###############################################################
#  Generated by:      Cadence Innovus 21.35-s114_1
#  OS:                Linux x86_64(Host ID pc231.ee.hacettepe.edu.tr)
#  Generated on:      Wed Dec 24 14:22:01 2025
#  Design:            protection_macro
#  Command:           write_lef_abstract -5.7 outputs/protection_macro/protection_macro.lef
###############################################################

VERSION 5.7 ;

BUSBITCHARS "[]" ;
DIVIDERCHAR "/" ;

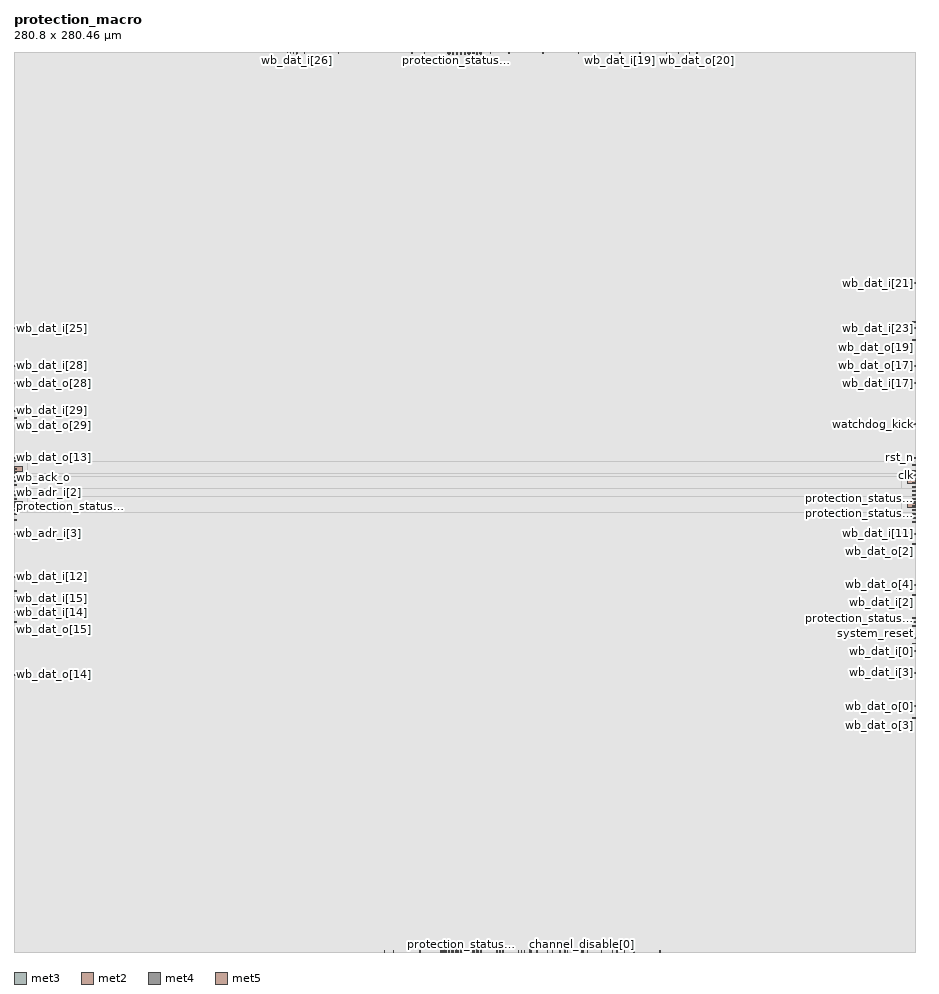
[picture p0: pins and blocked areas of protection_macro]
MACRO protection_macro
  CLASS BLOCK ;
  SIZE 280.800000 BY 280.460000 ;
  FOREIGN protection_macro 0.000000 0.000000 ;
  ORIGIN 0 0 ;
  SYMMETRY X Y R90 ;
  PIN clk
    DIRECTION INPUT ;
    USE SIGNAL ;
    PORT
      LAYER met3 ;
        RECT 280.000000 148.450000 280.800000 148.750000 ;
    END
  END clk
  PIN rst_n
    DIRECTION INPUT ;
    USE SIGNAL ;
    PORT
      LAYER met3 ;
        RECT 280.000000 151.500000 280.800000 151.800000 ;
    END
  END rst_n
  PIN wb_adr_i[31]
    DIRECTION INPUT ;
    USE SIGNAL ;
    PORT
      LAYER met2 ;
        RECT 142.250000 279.975000 142.390000 280.460000 ;
    END
  END wb_adr_i[31]
  PIN wb_adr_i[30]
    DIRECTION INPUT ;
    USE SIGNAL ;
    PORT
      LAYER met2 ;
        RECT 138.410000 0.000000 138.550000 0.485000 ;
    END
  END wb_adr_i[30]
  PIN wb_adr_i[29]
    DIRECTION INPUT ;
    USE SIGNAL ;
    PORT
      LAYER met2 ;
        RECT 142.250000 0.000000 142.390000 0.485000 ;
    END
  END wb_adr_i[29]
  PIN wb_adr_i[28]
    DIRECTION INPUT ;
    USE SIGNAL ;
    PORT
      LAYER met4 ;
        RECT 137.850000 279.660000 138.150000 280.460000 ;
    END
  END wb_adr_i[28]
  PIN wb_adr_i[27]
    DIRECTION INPUT ;
    USE SIGNAL ;
    PORT
      LAYER met4 ;
        RECT 137.850000 0.000000 138.150000 0.800000 ;
    END
  END wb_adr_i[27]
  PIN wb_adr_i[26]
    DIRECTION INPUT ;
    USE SIGNAL ;
    PORT
      LAYER met3 ;
        RECT 0.000000 142.350000 0.800000 142.650000 ;
    END
  END wb_adr_i[26]
  PIN wb_adr_i[25]
    DIRECTION INPUT ;
    USE SIGNAL ;
    PORT
      LAYER met3 ;
        RECT 280.000000 142.350000 280.800000 142.650000 ;
    END
  END wb_adr_i[25]
  PIN wb_adr_i[24]
    DIRECTION INPUT ;
    USE SIGNAL ;
    PORT
      LAYER met4 ;
        RECT 142.770000 279.660000 143.070000 280.460000 ;
    END
  END wb_adr_i[24]
  PIN wb_adr_i[23]
    DIRECTION INPUT ;
    USE SIGNAL ;
    PORT
      LAYER met4 ;
        RECT 142.770000 0.000000 143.070000 0.800000 ;
    END
  END wb_adr_i[23]
  PIN wb_adr_i[22]
    DIRECTION INPUT ;
    USE SIGNAL ;
    PORT
      LAYER met3 ;
        RECT 0.000000 137.470000 0.800000 137.770000 ;
    END
  END wb_adr_i[22]
  PIN wb_adr_i[21]
    DIRECTION INPUT ;
    USE SIGNAL ;
    PORT
      LAYER met3 ;
        RECT 280.000000 137.470000 280.800000 137.770000 ;
    END
  END wb_adr_i[21]
  PIN wb_adr_i[20]
    DIRECTION INPUT ;
    USE SIGNAL ;
    PORT
      LAYER met2 ;
        RECT 143.210000 279.975000 143.350000 280.460000 ;
    END
  END wb_adr_i[20]
  PIN wb_adr_i[19]
    DIRECTION INPUT ;
    USE SIGNAL ;
    PORT
      LAYER met2 ;
        RECT 137.450000 0.000000 137.590000 0.485000 ;
    END
  END wb_adr_i[19]
  PIN wb_adr_i[18]
    DIRECTION INPUT ;
    USE SIGNAL ;
    PORT
      LAYER met2 ;
        RECT 143.210000 0.000000 143.350000 0.485000 ;
    END
  END wb_adr_i[18]
  PIN wb_adr_i[17]
    DIRECTION INPUT ;
    USE SIGNAL ;
    PORT
      LAYER met2 ;
        RECT 136.970000 279.975000 137.110000 280.460000 ;
    END
  END wb_adr_i[17]
  PIN wb_adr_i[16]
    DIRECTION INPUT ;
    USE SIGNAL ;
    PORT
      LAYER met4 ;
        RECT 136.620000 279.660000 136.920000 280.460000 ;
    END
  END wb_adr_i[16]
  PIN wb_adr_i[15]
    DIRECTION INPUT ;
    USE SIGNAL ;
    PORT
      LAYER met2 ;
        RECT 136.490000 0.000000 136.630000 0.485000 ;
    END
  END wb_adr_i[15]
  PIN wb_adr_i[14]
    DIRECTION INPUT ;
    USE SIGNAL ;
    PORT
      LAYER met4 ;
        RECT 136.620000 0.000000 136.920000 0.800000 ;
    END
  END wb_adr_i[14]
  PIN wb_adr_i[13]
    DIRECTION INPUT ;
    USE SIGNAL ;
    PORT
      LAYER met3 ;
        RECT 0.000000 143.570000 0.800000 143.870000 ;
    END
  END wb_adr_i[13]
  PIN wb_adr_i[12]
    DIRECTION INPUT ;
    USE SIGNAL ;
    PORT
      LAYER met3 ;
        RECT 280.000000 143.570000 280.800000 143.870000 ;
    END
  END wb_adr_i[12]
  PIN wb_adr_i[11]
    DIRECTION INPUT ;
    USE SIGNAL ;
    PORT
      LAYER met2 ;
        RECT 144.170000 279.975000 144.310000 280.460000 ;
    END
  END wb_adr_i[11]
  PIN wb_adr_i[10]
    DIRECTION INPUT ;
    USE SIGNAL ;
    PORT
      LAYER met4 ;
        RECT 144.000000 279.660000 144.300000 280.460000 ;
    END
  END wb_adr_i[10]
  PIN wb_adr_i[9]
    DIRECTION INPUT ;
    USE SIGNAL ;
    PORT
      LAYER met4 ;
        RECT 144.000000 0.000000 144.300000 0.800000 ;
    END
  END wb_adr_i[9]
  PIN wb_adr_i[8]
    DIRECTION INPUT ;
    USE SIGNAL ;
    PORT
      LAYER met3 ;
        RECT 0.000000 136.250000 0.800000 136.550000 ;
    END
  END wb_adr_i[8]
  PIN wb_adr_i[7]
    DIRECTION INPUT ;
    USE SIGNAL ;
    PORT
      LAYER met2 ;
        RECT 135.530000 0.000000 135.670000 0.485000 ;
    END
  END wb_adr_i[7]
  PIN wb_adr_i[6]
    DIRECTION INPUT ;
    USE SIGNAL ;
    PORT
      LAYER met3 ;
        RECT 0.000000 134.420000 0.800000 134.720000 ;
    END
  END wb_adr_i[6]
  PIN wb_adr_i[5]
    DIRECTION INPUT ;
    USE SIGNAL ;
    PORT
      LAYER met4 ;
        RECT 135.390000 0.000000 135.690000 0.800000 ;
    END
  END wb_adr_i[5]
  PIN wb_adr_i[4]
    DIRECTION INPUT ;
    USE SIGNAL ;
    PORT
      LAYER met2 ;
        RECT 134.570000 0.000000 134.710000 0.485000 ;
    END
  END wb_adr_i[4]
  PIN wb_adr_i[3]
    DIRECTION INPUT ;
    USE SIGNAL ;
    PORT
      LAYER met3 ;
        RECT 0.000000 130.150000 0.800000 130.450000 ;
    END
  END wb_adr_i[3]
  PIN wb_adr_i[2]
    DIRECTION INPUT ;
    USE SIGNAL ;
    PORT
      LAYER met3 ;
        RECT 0.000000 145.400000 0.800000 145.700000 ;
    END
  END wb_adr_i[2]
  PIN wb_adr_i[1]
    DIRECTION INPUT ;
    USE SIGNAL ;
    PORT
      LAYER met3 ;
        RECT 280.000000 136.250000 280.800000 136.550000 ;
    END
  END wb_adr_i[1]
  PIN wb_adr_i[0]
    DIRECTION INPUT ;
    USE SIGNAL ;
    PORT
      LAYER met2 ;
        RECT 136.010000 279.975000 136.150000 280.460000 ;
    END
  END wb_adr_i[0]
  PIN wb_dat_o[31]
    DIRECTION OUTPUT ;
    USE SIGNAL ;
    PORT
      LAYER met3 ;
        RECT 0.000000 152.720000 0.800000 153.020000 ;
    END
  END wb_dat_o[31]
  PIN wb_dat_o[30]
    DIRECTION OUTPUT ;
    USE SIGNAL ;
    PORT
      LAYER met2 ;
        RECT 124.010000 279.975000 124.150000 280.460000 ;
    END
  END wb_dat_o[30]
  PIN wb_dat_o[29]
    DIRECTION OUTPUT ;
    USE SIGNAL ;
    PORT
      LAYER met3 ;
        RECT 0.000000 166.140000 0.800000 166.440000 ;
    END
  END wb_dat_o[29]
  PIN wb_dat_o[28]
    DIRECTION OUTPUT ;
    USE SIGNAL ;
    PORT
      LAYER met3 ;
        RECT 0.000000 177.120000 0.800000 177.420000 ;
    END
  END wb_dat_o[28]
  PIN wb_dat_o[27]
    DIRECTION OUTPUT ;
    USE SIGNAL ;
    PORT
      LAYER met2 ;
        RECT 86.090000 279.975000 86.230000 280.460000 ;
    END
  END wb_dat_o[27]
  PIN wb_dat_o[26]
    DIRECTION OUTPUT ;
    USE SIGNAL ;
    PORT
      LAYER met2 ;
        RECT 87.050000 279.975000 87.190000 280.460000 ;
    END
  END wb_dat_o[26]
  PIN wb_dat_o[25]
    DIRECTION OUTPUT ;
    USE SIGNAL ;
    PORT
      LAYER met2 ;
        RECT 100.970000 279.975000 101.110000 280.460000 ;
    END
  END wb_dat_o[25]
  PIN wb_dat_o[24]
    DIRECTION OUTPUT ;
    USE SIGNAL ;
    PORT
      LAYER met2 ;
        RECT 90.410000 279.975000 90.550000 280.460000 ;
    END
  END wb_dat_o[24]
  PIN wb_dat_o[23]
    DIRECTION OUTPUT ;
    USE SIGNAL ;
    PORT
      LAYER met3 ;
        RECT 280.000000 196.030000 280.800000 196.330000 ;
    END
  END wb_dat_o[23]
  PIN wb_dat_o[22]
    DIRECTION OUTPUT ;
    USE SIGNAL ;
    PORT
      LAYER met2 ;
        RECT 203.210000 279.975000 203.350000 280.460000 ;
    END
  END wb_dat_o[22]
  PIN wb_dat_o[21]
    DIRECTION OUTPUT ;
    USE SIGNAL ;
    PORT
      LAYER met2 ;
        RECT 195.050000 279.975000 195.190000 280.460000 ;
    END
  END wb_dat_o[21]
  PIN wb_dat_o[20]
    DIRECTION OUTPUT ;
    USE SIGNAL ;
    PORT
      LAYER met2 ;
        RECT 212.810000 279.975000 212.950000 280.460000 ;
    END
  END wb_dat_o[20]
  PIN wb_dat_o[19]
    DIRECTION OUTPUT ;
    USE SIGNAL ;
    PORT
      LAYER met3 ;
        RECT 280.000000 190.540000 280.800000 190.840000 ;
    END
  END wb_dat_o[19]
  PIN wb_dat_o[18]
    DIRECTION OUTPUT ;
    USE SIGNAL ;
    PORT
      LAYER met2 ;
        RECT 164.810000 279.975000 164.950000 280.460000 ;
    END
  END wb_dat_o[18]
  PIN wb_dat_o[17]
    DIRECTION OUTPUT ;
    USE SIGNAL ;
    PORT
      LAYER met3 ;
        RECT 280.000000 182.610000 280.800000 182.910000 ;
    END
  END wb_dat_o[17]
  PIN wb_dat_o[16]
    DIRECTION OUTPUT ;
    USE SIGNAL ;
    PORT
      LAYER met3 ;
        RECT 280.000000 153.940000 280.800000 154.240000 ;
    END
  END wb_dat_o[16]
  PIN wb_dat_o[15]
    DIRECTION OUTPUT ;
    USE SIGNAL ;
    PORT
      LAYER met3 ;
        RECT 0.000000 102.700000 0.800000 103.000000 ;
    END
  END wb_dat_o[15]
  PIN wb_dat_o[14]
    DIRECTION OUTPUT ;
    USE SIGNAL ;
    PORT
      LAYER met3 ;
        RECT 0.000000 86.230000 0.800000 86.530000 ;
    END
  END wb_dat_o[14]
  PIN wb_dat_o[13]
    DIRECTION OUTPUT ;
    USE SIGNAL ;
    PORT
      LAYER met3 ;
        RECT 0.000000 153.940000 0.800000 154.240000 ;
    END
  END wb_dat_o[13]
  PIN wb_dat_o[12]
    DIRECTION OUTPUT ;
    USE SIGNAL ;
    PORT
      LAYER met3 ;
        RECT 0.000000 110.630000 0.800000 110.930000 ;
    END
  END wb_dat_o[12]
  PIN wb_dat_o[11]
    DIRECTION OUTPUT ;
    USE SIGNAL ;
    PORT
      LAYER met3 ;
        RECT 280.000000 146.010000 280.800000 146.310000 ;
    END
  END wb_dat_o[11]
  PIN wb_dat_o[10]
    DIRECTION OUTPUT ;
    USE SIGNAL ;
    PORT
      LAYER met5 ;
        RECT 278.300000 145.970000 280.800000 147.570000 ;
    END
  END wb_dat_o[10]
  PIN wb_dat_o[9]
    DIRECTION OUTPUT ;
    USE SIGNAL ;
    PORT
      LAYER met4 ;
        RECT 160.605000 0.000000 160.905000 0.800000 ;
    END
  END wb_dat_o[9]
  PIN wb_dat_o[8]
    DIRECTION OUTPUT ;
    USE SIGNAL ;
    PORT
      LAYER met3 ;
        RECT 280.000000 147.230000 280.800000 147.530000 ;
    END
  END wb_dat_o[8]
  PIN wb_dat_o[7]
    DIRECTION OUTPUT ;
    USE SIGNAL ;
    PORT
      LAYER met2 ;
        RECT 126.410000 0.000000 126.550000 0.485000 ;
    END
  END wb_dat_o[7]
  PIN wb_dat_o[6]
    DIRECTION OUTPUT ;
    USE SIGNAL ;
    PORT
      LAYER met2 ;
        RECT 133.610000 0.000000 133.750000 0.485000 ;
    END
  END wb_dat_o[6]
  PIN wb_dat_o[5]
    DIRECTION OUTPUT ;
    USE SIGNAL ;
    PORT
      LAYER met4 ;
        RECT 132.930000 0.000000 133.230000 0.800000 ;
    END
  END wb_dat_o[5]
  PIN wb_dat_o[4]
    DIRECTION OUTPUT ;
    USE SIGNAL ;
    PORT
      LAYER met3 ;
        RECT 280.000000 114.290000 280.800000 114.590000 ;
    END
  END wb_dat_o[4]
  PIN wb_dat_o[3]
    DIRECTION OUTPUT ;
    USE SIGNAL ;
    PORT
      LAYER met3 ;
        RECT 280.000000 72.810000 280.800000 73.110000 ;
    END
  END wb_dat_o[3]
  PIN wb_dat_o[2]
    DIRECTION OUTPUT ;
    USE SIGNAL ;
    PORT
      LAYER met3 ;
        RECT 280.000000 127.100000 280.800000 127.400000 ;
    END
  END wb_dat_o[2]
  PIN wb_dat_o[1]
    DIRECTION OUTPUT ;
    USE SIGNAL ;
    PORT
      LAYER met3 ;
        RECT 280.000000 149.670000 280.800000 149.970000 ;
    END
  END wb_dat_o[1]
  PIN wb_dat_o[0]
    DIRECTION OUTPUT ;
    USE SIGNAL ;
    PORT
      LAYER met3 ;
        RECT 280.000000 76.470000 280.800000 76.770000 ;
    END
  END wb_dat_o[0]
  PIN wb_dat_i[31]
    DIRECTION INPUT ;
    USE SIGNAL ;
    PORT
      LAYER met2 ;
        RECT 127.850000 279.975000 127.990000 280.460000 ;
    END
  END wb_dat_i[31]
  PIN wb_dat_i[30]
    DIRECTION INPUT ;
    USE SIGNAL ;
    PORT
      LAYER met2 ;
        RECT 148.490000 279.975000 148.630000 280.460000 ;
    END
  END wb_dat_i[30]
  PIN wb_dat_i[29]
    DIRECTION INPUT ;
    USE SIGNAL ;
    PORT
      LAYER met3 ;
        RECT 0.000000 168.580000 0.800000 168.880000 ;
    END
  END wb_dat_i[29]
  PIN wb_dat_i[28]
    DIRECTION INPUT ;
    USE SIGNAL ;
    PORT
      LAYER met3 ;
        RECT 0.000000 182.610000 0.800000 182.910000 ;
    END
  END wb_dat_i[28]
  PIN wb_dat_i[27]
    DIRECTION INPUT ;
    USE SIGNAL ;
    PORT
      LAYER met2 ;
        RECT 85.130000 279.975000 85.270000 280.460000 ;
    END
  END wb_dat_i[27]
  PIN wb_dat_i[26]
    DIRECTION INPUT ;
    USE SIGNAL ;
    PORT
      LAYER met2 ;
        RECT 88.010000 279.975000 88.150000 280.460000 ;
    END
  END wb_dat_i[26]
  PIN wb_dat_i[25]
    DIRECTION INPUT ;
    USE SIGNAL ;
    PORT
      LAYER met3 ;
        RECT 0.000000 194.200000 0.800000 194.500000 ;
    END
  END wb_dat_i[25]
  PIN wb_dat_i[24]
    DIRECTION INPUT ;
    USE SIGNAL ;
    PORT
      LAYER met4 ;
        RECT 88.035000 279.660000 88.335000 280.460000 ;
    END
  END wb_dat_i[24]
  PIN wb_dat_i[23]
    DIRECTION INPUT ;
    USE SIGNAL ;
    PORT
      LAYER met3 ;
        RECT 280.000000 194.200000 280.800000 194.500000 ;
    END
  END wb_dat_i[23]
  PIN wb_dat_i[22]
    DIRECTION INPUT ;
    USE SIGNAL ;
    PORT
      LAYER met2 ;
        RECT 207.050000 279.975000 207.190000 280.460000 ;
    END
  END wb_dat_i[22]
  PIN wb_dat_i[21]
    DIRECTION INPUT ;
    USE SIGNAL ;
    PORT
      LAYER met3 ;
        RECT 280.000000 208.230000 280.800000 208.530000 ;
    END
  END wb_dat_i[21]
  PIN wb_dat_i[20]
    DIRECTION INPUT ;
    USE SIGNAL ;
    PORT
      LAYER met2 ;
        RECT 210.410000 279.975000 210.550000 280.460000 ;
    END
  END wb_dat_i[20]
  PIN wb_dat_i[19]
    DIRECTION INPUT ;
    USE SIGNAL ;
    PORT
      LAYER met2 ;
        RECT 188.810000 279.975000 188.950000 280.460000 ;
    END
  END wb_dat_i[19]
  PIN wb_dat_i[18]
    DIRECTION INPUT ;
    USE SIGNAL ;
    PORT
      LAYER met2 ;
        RECT 175.850000 279.975000 175.990000 280.460000 ;
    END
  END wb_dat_i[18]
  PIN wb_dat_i[17]
    DIRECTION INPUT ;
    USE SIGNAL ;
    PORT
      LAYER met3 ;
        RECT 280.000000 177.120000 280.800000 177.420000 ;
    END
  END wb_dat_i[17]
  PIN wb_dat_i[16]
    DIRECTION INPUT ;
    USE SIGNAL ;
    PORT
      LAYER met2 ;
        RECT 154.250000 279.975000 154.390000 280.460000 ;
    END
  END wb_dat_i[16]
  PIN wb_dat_i[15]
    DIRECTION INPUT ;
    USE SIGNAL ;
    PORT
      LAYER met3 ;
        RECT 0.000000 112.460000 0.800000 112.760000 ;
    END
  END wb_dat_i[15]
  PIN wb_dat_i[14]
    DIRECTION INPUT ;
    USE SIGNAL ;
    PORT
      LAYER met3 ;
        RECT 0.000000 105.750000 0.800000 106.050000 ;
    END
  END wb_dat_i[14]
  PIN wb_dat_i[13]
    DIRECTION INPUT ;
    USE SIGNAL ;
    PORT
      LAYER met3 ;
        RECT 0.000000 146.620000 0.800000 146.920000 ;
    END
  END wb_dat_i[13]
  PIN wb_dat_i[12]
    DIRECTION INPUT ;
    USE SIGNAL ;
    PORT
      LAYER met3 ;
        RECT 0.000000 116.730000 0.800000 117.030000 ;
    END
  END wb_dat_i[12]
  PIN wb_dat_i[11]
    DIRECTION INPUT ;
    USE SIGNAL ;
    PORT
      LAYER met3 ;
        RECT 280.000000 130.150000 280.800000 130.450000 ;
    END
  END wb_dat_i[11]
  PIN wb_dat_i[10]
    DIRECTION INPUT ;
    USE SIGNAL ;
    PORT
      LAYER met3 ;
        RECT 280.000000 135.030000 280.800000 135.330000 ;
    END
  END wb_dat_i[10]
  PIN wb_dat_i[9]
    DIRECTION INPUT ;
    USE SIGNAL ;
    PORT
      LAYER met2 ;
        RECT 150.410000 0.000000 150.550000 0.485000 ;
    END
  END wb_dat_i[9]
  PIN wb_dat_i[8]
    DIRECTION INPUT ;
    USE SIGNAL ;
    PORT
      LAYER met3 ;
        RECT 280.000000 133.810000 280.800000 134.110000 ;
    END
  END wb_dat_i[8]
  PIN wb_dat_i[7]
    DIRECTION INPUT ;
    USE SIGNAL ;
    PORT
      LAYER met2 ;
        RECT 118.250000 0.000000 118.390000 0.485000 ;
    END
  END wb_dat_i[7]
  PIN wb_dat_i[6]
    DIRECTION INPUT ;
    USE SIGNAL ;
    PORT
      LAYER met2 ;
        RECT 115.370000 0.000000 115.510000 0.485000 ;
    END
  END wb_dat_i[6]
  PIN wb_dat_i[5]
    DIRECTION INPUT ;
    USE SIGNAL ;
    PORT
      LAYER met4 ;
        RECT 134.160000 0.000000 134.460000 0.800000 ;
    END
  END wb_dat_i[5]
  PIN wb_dat_i[4]
    DIRECTION INPUT ;
    USE SIGNAL ;
    PORT
      LAYER met3 ;
        RECT 280.000000 95.990000 280.800000 96.290000 ;
    END
  END wb_dat_i[4]
  PIN wb_dat_i[3]
    DIRECTION INPUT ;
    USE SIGNAL ;
    PORT
      LAYER met3 ;
        RECT 280.000000 86.840000 280.800000 87.140000 ;
    END
  END wb_dat_i[3]
  PIN wb_dat_i[2]
    DIRECTION INPUT ;
    USE SIGNAL ;
    PORT
      LAYER met3 ;
        RECT 280.000000 111.240000 280.800000 111.540000 ;
    END
  END wb_dat_i[2]
  PIN wb_dat_i[1]
    DIRECTION INPUT ;
    USE SIGNAL ;
    PORT
      LAYER met3 ;
        RECT 280.000000 144.790000 280.800000 145.090000 ;
    END
  END wb_dat_i[1]
  PIN wb_dat_i[0]
    DIRECTION INPUT ;
    USE SIGNAL ;
    PORT
      LAYER met3 ;
        RECT 280.000000 93.550000 280.800000 93.850000 ;
    END
  END wb_dat_i[0]
  PIN wb_we_i
    DIRECTION INPUT ;
    USE SIGNAL ;
    PORT
      LAYER met3 ;
        RECT 0.000000 150.280000 0.800000 150.580000 ;
    END
  END wb_we_i
  PIN wb_sel_i[3]
    DIRECTION INPUT ;
    USE SIGNAL ;
    PORT
      LAYER met2 ;
        RECT 145.130000 279.975000 145.270000 280.460000 ;
    END
  END wb_sel_i[3]
  PIN wb_sel_i[2]
    DIRECTION INPUT ;
    USE SIGNAL ;
    PORT
      LAYER met4 ;
        RECT 135.390000 279.660000 135.690000 280.460000 ;
    END
  END wb_sel_i[2]
  PIN wb_sel_i[1]
    DIRECTION INPUT ;
    USE SIGNAL ;
    PORT
      LAYER met4 ;
        RECT 145.230000 279.660000 145.530000 280.460000 ;
    END
  END wb_sel_i[1]
  PIN wb_sel_i[0]
    DIRECTION INPUT ;
    USE SIGNAL ;
    PORT
      LAYER met4 ;
        RECT 145.230000 0.000000 145.530000 0.800000 ;
    END
  END wb_sel_i[0]
  PIN wb_cyc_i
    DIRECTION INPUT ;
    USE SIGNAL ;
    PORT
      LAYER met5 ;
        RECT 0.000000 149.630000 2.500000 151.230000 ;
    END
  END wb_cyc_i
  PIN wb_stb_i
    DIRECTION INPUT ;
    USE SIGNAL ;
    PORT
      LAYER met3 ;
        RECT 0.000000 149.060000 0.800000 149.360000 ;
    END
  END wb_stb_i
  PIN wb_ack_o
    DIRECTION OUTPUT ;
    USE SIGNAL ;
    PORT
      LAYER met3 ;
        RECT 0.000000 147.840000 0.800000 148.140000 ;
    END
  END wb_ack_o
  PIN wb_err_o
    DIRECTION OUTPUT ;
    USE SIGNAL ;
    PORT
      LAYER met2 ;
        RECT 135.050000 279.975000 135.190000 280.460000 ;
    END
  END wb_err_o
  PIN current_sense[3]
    DIRECTION INPUT ;
    USE SIGNAL ;
    PORT
      LAYER met2 ;
        RECT 144.650000 0.000000 144.790000 0.485000 ;
    END
  END current_sense[3]
  PIN current_sense[2]
    DIRECTION INPUT ;
    USE SIGNAL ;
    PORT
      LAYER met2 ;
        RECT 158.090000 0.000000 158.230000 0.485000 ;
    END
  END current_sense[2]
  PIN current_sense[1]
    DIRECTION INPUT ;
    USE SIGNAL ;
    PORT
      LAYER met2 ;
        RECT 152.330000 0.000000 152.470000 0.485000 ;
    END
  END current_sense[1]
  PIN current_sense[0]
    DIRECTION INPUT ;
    USE SIGNAL ;
    PORT
      LAYER met2 ;
        RECT 167.690000 0.000000 167.830000 0.485000 ;
    END
  END current_sense[0]
  PIN voltage_sense[3]
    DIRECTION INPUT ;
    USE SIGNAL ;
    PORT
      LAYER met2 ;
        RECT 186.410000 0.000000 186.550000 0.485000 ;
    END
  END voltage_sense[3]
  PIN voltage_sense[2]
    DIRECTION INPUT ;
    USE SIGNAL ;
    PORT
      LAYER met2 ;
        RECT 193.130000 0.000000 193.270000 0.485000 ;
    END
  END voltage_sense[2]
  PIN voltage_sense[1]
    DIRECTION INPUT ;
    USE SIGNAL ;
    PORT
      LAYER met4 ;
        RECT 177.210000 0.000000 177.510000 0.800000 ;
    END
  END voltage_sense[1]
  PIN voltage_sense[0]
    DIRECTION INPUT ;
    USE SIGNAL ;
    PORT
      LAYER met2 ;
        RECT 201.290000 0.000000 201.430000 0.485000 ;
    END
  END voltage_sense[0]
  PIN thermal_alert
    DIRECTION INPUT ;
    USE SIGNAL ;
    PORT
      LAYER met2 ;
        RECT 190.250000 0.000000 190.390000 0.485000 ;
    END
  END thermal_alert
  PIN emergency_stop
    DIRECTION OUTPUT ;
    USE SIGNAL ;
    PORT
      LAYER met2 ;
        RECT 170.090000 0.000000 170.230000 0.485000 ;
    END
  END emergency_stop
  PIN channel_disable[3]
    DIRECTION OUTPUT ;
    USE SIGNAL ;
    PORT
      LAYER met2 ;
        RECT 159.050000 0.000000 159.190000 0.485000 ;
    END
  END channel_disable[3]
  PIN channel_disable[2]
    DIRECTION OUTPUT ;
    USE SIGNAL ;
    PORT
      LAYER met2 ;
        RECT 171.530000 0.000000 171.670000 0.485000 ;
    END
  END channel_disable[2]
  PIN channel_disable[1]
    DIRECTION OUTPUT ;
    USE SIGNAL ;
    PORT
      LAYER met2 ;
        RECT 162.890000 0.000000 163.030000 0.485000 ;
    END
  END channel_disable[1]
  PIN channel_disable[0]
    DIRECTION OUTPUT ;
    USE SIGNAL ;
    PORT
      LAYER met2 ;
        RECT 176.810000 0.000000 176.950000 0.485000 ;
    END
  END channel_disable[0]
  PIN system_reset
    DIRECTION OUTPUT ;
    USE SIGNAL ;
    PORT
      LAYER met3 ;
        RECT 280.000000 101.480000 280.800000 101.780000 ;
    END
  END system_reset
  PIN watchdog_kick
    DIRECTION INPUT ;
    USE SIGNAL ;
    PORT
      LAYER met3 ;
        RECT 280.000000 164.310000 280.800000 164.610000 ;
    END
  END watchdog_kick
  PIN watchdog_timeout
    DIRECTION OUTPUT ;
    USE SIGNAL ;
    PORT
      LAYER met3 ;
        RECT 280.000000 102.700000 280.800000 103.000000 ;
    END
  END watchdog_timeout
  PIN irq
    DIRECTION OUTPUT ;
    USE SIGNAL ;
    PORT
      LAYER met2 ;
        RECT 166.250000 0.000000 166.390000 0.485000 ;
    END
  END irq
  PIN protection_status[31]
    DIRECTION OUTPUT ;
    USE SIGNAL ;
    PORT
      LAYER met2 ;
        RECT 140.330000 279.975000 140.470000 280.460000 ;
    END
  END protection_status[31]
  PIN protection_status[30]
    DIRECTION OUTPUT ;
    USE SIGNAL ;
    PORT
      LAYER met2 ;
        RECT 140.330000 0.000000 140.470000 0.485000 ;
    END
  END protection_status[30]
  PIN protection_status[29]
    DIRECTION OUTPUT ;
    USE SIGNAL ;
    PORT
      LAYER met4 ;
        RECT 140.310000 279.660000 140.610000 280.460000 ;
    END
  END protection_status[29]
  PIN protection_status[28]
    DIRECTION OUTPUT ;
    USE SIGNAL ;
    PORT
      LAYER met4 ;
        RECT 140.310000 0.000000 140.610000 0.800000 ;
    END
  END protection_status[28]
  PIN protection_status[27]
    DIRECTION OUTPUT ;
    USE SIGNAL ;
    PORT
      LAYER met3 ;
        RECT 0.000000 139.910000 0.800000 140.210000 ;
    END
  END protection_status[27]
  PIN protection_status[26]
    DIRECTION OUTPUT ;
    USE SIGNAL ;
    PORT
      LAYER met3 ;
        RECT 280.000000 139.910000 280.800000 140.210000 ;
    END
  END protection_status[26]
  PIN protection_status[25]
    DIRECTION OUTPUT ;
    USE SIGNAL ;
    PORT
      LAYER met5 ;
        RECT 0.000000 138.650000 2.500000 140.250000 ;
    END
  END protection_status[25]
  PIN protection_status[24]
    DIRECTION OUTPUT ;
    USE SIGNAL ;
    PORT
      LAYER met5 ;
        RECT 278.300000 138.650000 280.800000 140.250000 ;
    END
  END protection_status[24]
  PIN protection_status[23]
    DIRECTION OUTPUT ;
    USE SIGNAL ;
    PORT
      LAYER met2 ;
        RECT 139.370000 279.975000 139.510000 280.460000 ;
    END
  END protection_status[23]
  PIN protection_status[22]
    DIRECTION OUTPUT ;
    USE SIGNAL ;
    PORT
      LAYER met2 ;
        RECT 141.290000 279.975000 141.430000 280.460000 ;
    END
  END protection_status[22]
  PIN protection_status[21]
    DIRECTION OUTPUT ;
    USE SIGNAL ;
    PORT
      LAYER met2 ;
        RECT 139.370000 0.000000 139.510000 0.485000 ;
    END
  END protection_status[21]
  PIN protection_status[20]
    DIRECTION OUTPUT ;
    USE SIGNAL ;
    PORT
      LAYER met2 ;
        RECT 141.290000 0.000000 141.430000 0.485000 ;
    END
  END protection_status[20]
  PIN protection_status[19]
    DIRECTION OUTPUT ;
    USE SIGNAL ;
    PORT
      LAYER met4 ;
        RECT 139.080000 279.660000 139.380000 280.460000 ;
    END
  END protection_status[19]
  PIN protection_status[18]
    DIRECTION OUTPUT ;
    USE SIGNAL ;
    PORT
      LAYER met4 ;
        RECT 139.080000 0.000000 139.380000 0.800000 ;
    END
  END protection_status[18]
  PIN protection_status[17]
    DIRECTION OUTPUT ;
    USE SIGNAL ;
    PORT
      LAYER met3 ;
        RECT 0.000000 141.130000 0.800000 141.430000 ;
    END
  END protection_status[17]
  PIN protection_status[16]
    DIRECTION OUTPUT ;
    USE SIGNAL ;
    PORT
      LAYER met2 ;
        RECT 137.930000 279.975000 138.070000 280.460000 ;
    END
  END protection_status[16]
  PIN protection_status[15]
    DIRECTION OUTPUT ;
    USE SIGNAL ;
    PORT
      LAYER met3 ;
        RECT 280.000000 141.130000 280.800000 141.430000 ;
    END
  END protection_status[15]
  PIN protection_status[14]
    DIRECTION OUTPUT ;
    USE SIGNAL ;
    PORT
      LAYER met4 ;
        RECT 141.540000 279.660000 141.840000 280.460000 ;
    END
  END protection_status[14]
  PIN protection_status[13]
    DIRECTION OUTPUT ;
    USE SIGNAL ;
    PORT
      LAYER met4 ;
        RECT 141.540000 0.000000 141.840000 0.800000 ;
    END
  END protection_status[13]
  PIN protection_status[12]
    DIRECTION OUTPUT ;
    USE SIGNAL ;
    PORT
      LAYER met3 ;
        RECT 0.000000 138.690000 0.800000 138.990000 ;
    END
  END protection_status[12]
  PIN protection_status[11]
    DIRECTION OUTPUT ;
    USE SIGNAL ;
    PORT
      LAYER met2 ;
        RECT 175.850000 0.000000 175.990000 0.485000 ;
    END
  END protection_status[11]
  PIN protection_status[10]
    DIRECTION OUTPUT ;
    USE SIGNAL ;
    PORT
      LAYER met2 ;
        RECT 178.730000 0.000000 178.870000 0.485000 ;
    END
  END protection_status[10]
  PIN protection_status[9]
    DIRECTION OUTPUT ;
    USE SIGNAL ;
    PORT
      LAYER met2 ;
        RECT 172.490000 0.000000 172.630000 0.485000 ;
    END
  END protection_status[9]
  PIN protection_status[8]
    DIRECTION OUTPUT ;
    USE SIGNAL ;
    PORT
      LAYER met2 ;
        RECT 187.850000 0.000000 187.990000 0.485000 ;
    END
  END protection_status[8]
  PIN protection_status[7]
    DIRECTION OUTPUT ;
    USE SIGNAL ;
    PORT
      LAYER met2 ;
        RECT 151.370000 0.000000 151.510000 0.485000 ;
    END
  END protection_status[7]
  PIN protection_status[6]
    DIRECTION OUTPUT ;
    USE SIGNAL ;
    PORT
      LAYER met2 ;
        RECT 160.970000 0.000000 161.110000 0.485000 ;
    END
  END protection_status[6]
  PIN protection_status[5]
    DIRECTION OUTPUT ;
    USE SIGNAL ;
    PORT
      LAYER met2 ;
        RECT 157.130000 0.000000 157.270000 0.485000 ;
    END
  END protection_status[5]
  PIN protection_status[4]
    DIRECTION OUTPUT ;
    USE SIGNAL ;
    PORT
      LAYER met4 ;
        RECT 171.675000 0.000000 171.975000 0.800000 ;
    END
  END protection_status[4]
  PIN protection_status[3]
    DIRECTION OUTPUT ;
    USE SIGNAL ;
    PORT
      LAYER met3 ;
        RECT 280.000000 138.690000 280.800000 138.990000 ;
    END
  END protection_status[3]
  PIN protection_status[2]
    DIRECTION OUTPUT ;
    USE SIGNAL ;
    PORT
      LAYER met3 ;
        RECT 280.000000 103.920000 280.800000 104.220000 ;
    END
  END protection_status[2]
  PIN protection_status[1]
    DIRECTION OUTPUT ;
    USE SIGNAL ;
    PORT
      LAYER met2 ;
        RECT 183.050000 0.000000 183.190000 0.485000 ;
    END
  END protection_status[1]
  PIN protection_status[0]
    DIRECTION OUTPUT ;
    USE SIGNAL ;
    PORT
      LAYER met3 ;
        RECT 280.000000 97.820000 280.800000 98.120000 ;
    END
  END protection_status[0]
  OBS
    LAYER met1 ;
      RECT 0.000000 0.000000 280.800000 280.460000 ;
    LAYER met2 ;
      RECT 213.090000 279.835000 280.800000 280.460000 ;
      RECT 210.690000 279.835000 212.670000 280.460000 ;
      RECT 207.330000 279.835000 210.270000 280.460000 ;
      RECT 203.490000 279.835000 206.910000 280.460000 ;
      RECT 195.330000 279.835000 203.070000 280.460000 ;
      RECT 189.090000 279.835000 194.910000 280.460000 ;
      RECT 176.130000 279.835000 188.670000 280.460000 ;
      RECT 165.090000 279.835000 175.710000 280.460000 ;
      RECT 154.530000 279.835000 164.670000 280.460000 ;
      RECT 148.770000 279.835000 154.110000 280.460000 ;
      RECT 145.410000 279.835000 148.350000 280.460000 ;
      RECT 144.450000 279.835000 144.990000 280.460000 ;
      RECT 143.490000 279.835000 144.030000 280.460000 ;
      RECT 142.530000 279.835000 143.070000 280.460000 ;
      RECT 141.570000 279.835000 142.110000 280.460000 ;
      RECT 140.610000 279.835000 141.150000 280.460000 ;
      RECT 139.650000 279.835000 140.190000 280.460000 ;
      RECT 138.210000 279.835000 139.230000 280.460000 ;
      RECT 137.250000 279.835000 137.790000 280.460000 ;
      RECT 136.290000 279.835000 136.830000 280.460000 ;
      RECT 135.330000 279.835000 135.870000 280.460000 ;
      RECT 128.130000 279.835000 134.910000 280.460000 ;
      RECT 124.290000 279.835000 127.710000 280.460000 ;
      RECT 101.250000 279.835000 123.870000 280.460000 ;
      RECT 90.690000 279.835000 100.830000 280.460000 ;
      RECT 88.290000 279.835000 90.270000 280.460000 ;
      RECT 87.330000 279.835000 87.870000 280.460000 ;
      RECT 86.370000 279.835000 86.910000 280.460000 ;
      RECT 85.410000 279.835000 85.950000 280.460000 ;
      RECT 0.000000 279.835000 84.990000 280.460000 ;
      RECT 0.000000 0.625000 280.800000 279.835000 ;
      RECT 201.570000 0.000000 280.800000 0.625000 ;
      RECT 193.410000 0.000000 201.150000 0.625000 ;
      RECT 190.530000 0.000000 192.990000 0.625000 ;
      RECT 188.130000 0.000000 190.110000 0.625000 ;
      RECT 186.690000 0.000000 187.710000 0.625000 ;
      RECT 183.330000 0.000000 186.270000 0.625000 ;
      RECT 179.010000 0.000000 182.910000 0.625000 ;
      RECT 177.090000 0.000000 178.590000 0.625000 ;
      RECT 176.130000 0.000000 176.670000 0.625000 ;
      RECT 172.770000 0.000000 175.710000 0.625000 ;
      RECT 171.810000 0.000000 172.350000 0.625000 ;
      RECT 170.370000 0.000000 171.390000 0.625000 ;
      RECT 167.970000 0.000000 169.950000 0.625000 ;
      RECT 166.530000 0.000000 167.550000 0.625000 ;
      RECT 163.170000 0.000000 166.110000 0.625000 ;
      RECT 161.250000 0.000000 162.750000 0.625000 ;
      RECT 159.330000 0.000000 160.830000 0.625000 ;
      RECT 158.370000 0.000000 158.910000 0.625000 ;
      RECT 157.410000 0.000000 157.950000 0.625000 ;
      RECT 152.610000 0.000000 156.990000 0.625000 ;
      RECT 151.650000 0.000000 152.190000 0.625000 ;
      RECT 150.690000 0.000000 151.230000 0.625000 ;
      RECT 144.930000 0.000000 150.270000 0.625000 ;
      RECT 143.490000 0.000000 144.510000 0.625000 ;
      RECT 142.530000 0.000000 143.070000 0.625000 ;
      RECT 141.570000 0.000000 142.110000 0.625000 ;
      RECT 140.610000 0.000000 141.150000 0.625000 ;
      RECT 139.650000 0.000000 140.190000 0.625000 ;
      RECT 138.690000 0.000000 139.230000 0.625000 ;
      RECT 137.730000 0.000000 138.270000 0.625000 ;
      RECT 136.770000 0.000000 137.310000 0.625000 ;
      RECT 135.810000 0.000000 136.350000 0.625000 ;
      RECT 134.850000 0.000000 135.390000 0.625000 ;
      RECT 133.890000 0.000000 134.430000 0.625000 ;
      RECT 126.690000 0.000000 133.470000 0.625000 ;
      RECT 118.530000 0.000000 126.270000 0.625000 ;
      RECT 115.650000 0.000000 118.110000 0.625000 ;
      RECT 0.000000 0.000000 115.230000 0.625000 ;
    LAYER met3 ;
      RECT 0.000000 208.830000 280.800000 280.460000 ;
      RECT 0.000000 207.930000 279.700000 208.830000 ;
      RECT 0.000000 196.630000 280.800000 207.930000 ;
      RECT 0.000000 195.730000 279.700000 196.630000 ;
      RECT 0.000000 194.800000 280.800000 195.730000 ;
      RECT 1.100000 193.900000 279.700000 194.800000 ;
      RECT 0.000000 191.140000 280.800000 193.900000 ;
      RECT 0.000000 190.240000 279.700000 191.140000 ;
      RECT 0.000000 183.210000 280.800000 190.240000 ;
      RECT 1.100000 182.310000 279.700000 183.210000 ;
      RECT 0.000000 177.720000 280.800000 182.310000 ;
      RECT 1.100000 176.820000 279.700000 177.720000 ;
      RECT 0.000000 169.180000 280.800000 176.820000 ;
      RECT 1.100000 168.280000 280.800000 169.180000 ;
      RECT 0.000000 166.740000 280.800000 168.280000 ;
      RECT 1.100000 165.840000 280.800000 166.740000 ;
      RECT 0.000000 164.910000 280.800000 165.840000 ;
      RECT 0.000000 164.010000 279.700000 164.910000 ;
      RECT 0.000000 154.540000 280.800000 164.010000 ;
      RECT 1.100000 153.640000 279.700000 154.540000 ;
      RECT 0.000000 153.320000 280.800000 153.640000 ;
      RECT 1.100000 152.420000 280.800000 153.320000 ;
      RECT 0.000000 152.100000 280.800000 152.420000 ;
      RECT 0.000000 151.200000 279.700000 152.100000 ;
      RECT 0.000000 150.880000 280.800000 151.200000 ;
      RECT 1.100000 150.270000 280.800000 150.880000 ;
      RECT 1.100000 149.980000 279.700000 150.270000 ;
      RECT 0.000000 149.660000 279.700000 149.980000 ;
      RECT 1.100000 149.370000 279.700000 149.660000 ;
      RECT 1.100000 149.050000 280.800000 149.370000 ;
      RECT 1.100000 148.760000 279.700000 149.050000 ;
      RECT 0.000000 148.440000 279.700000 148.760000 ;
      RECT 1.100000 148.150000 279.700000 148.440000 ;
      RECT 1.100000 147.830000 280.800000 148.150000 ;
      RECT 1.100000 147.540000 279.700000 147.830000 ;
      RECT 0.000000 147.220000 279.700000 147.540000 ;
      RECT 1.100000 146.930000 279.700000 147.220000 ;
      RECT 1.100000 146.610000 280.800000 146.930000 ;
      RECT 1.100000 146.320000 279.700000 146.610000 ;
      RECT 0.000000 146.000000 279.700000 146.320000 ;
      RECT 1.100000 145.710000 279.700000 146.000000 ;
      RECT 1.100000 145.390000 280.800000 145.710000 ;
      RECT 1.100000 145.100000 279.700000 145.390000 ;
      RECT 0.000000 144.490000 279.700000 145.100000 ;
      RECT 0.000000 144.170000 280.800000 144.490000 ;
      RECT 1.100000 143.270000 279.700000 144.170000 ;
      RECT 0.000000 142.950000 280.800000 143.270000 ;
      RECT 1.100000 142.050000 279.700000 142.950000 ;
      RECT 0.000000 141.730000 280.800000 142.050000 ;
      RECT 1.100000 140.830000 279.700000 141.730000 ;
      RECT 0.000000 140.510000 280.800000 140.830000 ;
      RECT 1.100000 139.610000 279.700000 140.510000 ;
      RECT 0.000000 139.290000 280.800000 139.610000 ;
      RECT 1.100000 138.390000 279.700000 139.290000 ;
      RECT 0.000000 138.070000 280.800000 138.390000 ;
      RECT 1.100000 137.170000 279.700000 138.070000 ;
      RECT 0.000000 136.850000 280.800000 137.170000 ;
      RECT 1.100000 135.950000 279.700000 136.850000 ;
      RECT 0.000000 135.630000 280.800000 135.950000 ;
      RECT 0.000000 135.020000 279.700000 135.630000 ;
      RECT 1.100000 134.730000 279.700000 135.020000 ;
      RECT 1.100000 134.410000 280.800000 134.730000 ;
      RECT 1.100000 134.120000 279.700000 134.410000 ;
      RECT 0.000000 133.510000 279.700000 134.120000 ;
      RECT 0.000000 130.750000 280.800000 133.510000 ;
      RECT 1.100000 129.850000 279.700000 130.750000 ;
      RECT 0.000000 127.700000 280.800000 129.850000 ;
      RECT 0.000000 126.800000 279.700000 127.700000 ;
      RECT 0.000000 117.330000 280.800000 126.800000 ;
      RECT 1.100000 116.430000 280.800000 117.330000 ;
      RECT 0.000000 114.890000 280.800000 116.430000 ;
      RECT 0.000000 113.990000 279.700000 114.890000 ;
      RECT 0.000000 113.060000 280.800000 113.990000 ;
      RECT 1.100000 112.160000 280.800000 113.060000 ;
      RECT 0.000000 111.840000 280.800000 112.160000 ;
      RECT 0.000000 111.230000 279.700000 111.840000 ;
      RECT 1.100000 110.940000 279.700000 111.230000 ;
      RECT 1.100000 110.330000 280.800000 110.940000 ;
      RECT 0.000000 106.350000 280.800000 110.330000 ;
      RECT 1.100000 105.450000 280.800000 106.350000 ;
      RECT 0.000000 104.520000 280.800000 105.450000 ;
      RECT 0.000000 103.620000 279.700000 104.520000 ;
      RECT 0.000000 103.300000 280.800000 103.620000 ;
      RECT 1.100000 102.400000 279.700000 103.300000 ;
      RECT 0.000000 102.080000 280.800000 102.400000 ;
      RECT 0.000000 101.180000 279.700000 102.080000 ;
      RECT 0.000000 98.420000 280.800000 101.180000 ;
      RECT 0.000000 97.520000 279.700000 98.420000 ;
      RECT 0.000000 96.590000 280.800000 97.520000 ;
      RECT 0.000000 95.690000 279.700000 96.590000 ;
      RECT 0.000000 94.150000 280.800000 95.690000 ;
      RECT 0.000000 93.250000 279.700000 94.150000 ;
      RECT 0.000000 87.440000 280.800000 93.250000 ;
      RECT 0.000000 86.830000 279.700000 87.440000 ;
      RECT 1.100000 86.540000 279.700000 86.830000 ;
      RECT 1.100000 85.930000 280.800000 86.540000 ;
      RECT 0.000000 77.070000 280.800000 85.930000 ;
      RECT 0.000000 76.170000 279.700000 77.070000 ;
      RECT 0.000000 73.410000 280.800000 76.170000 ;
      RECT 0.000000 72.510000 279.700000 73.410000 ;
      RECT 0.000000 0.000000 280.800000 72.510000 ;
    LAYER met4 ;
      RECT 145.830000 279.360000 280.800000 280.460000 ;
      RECT 144.600000 279.360000 144.930000 280.460000 ;
      RECT 143.370000 279.360000 143.700000 280.460000 ;
      RECT 142.140000 279.360000 142.470000 280.460000 ;
      RECT 140.910000 279.360000 141.240000 280.460000 ;
      RECT 139.680000 279.360000 140.010000 280.460000 ;
      RECT 138.450000 279.360000 138.780000 280.460000 ;
      RECT 137.220000 279.360000 137.550000 280.460000 ;
      RECT 135.990000 279.360000 136.320000 280.460000 ;
      RECT 88.635000 279.360000 135.090000 280.460000 ;
      RECT 0.000000 279.360000 87.735000 280.460000 ;
      RECT 0.000000 1.100000 280.800000 279.360000 ;
      RECT 177.810000 0.000000 280.800000 1.100000 ;
      RECT 172.275000 0.000000 176.910000 1.100000 ;
      RECT 161.205000 0.000000 171.375000 1.100000 ;
      RECT 145.830000 0.000000 160.305000 1.100000 ;
      RECT 144.600000 0.000000 144.930000 1.100000 ;
      RECT 143.370000 0.000000 143.700000 1.100000 ;
      RECT 142.140000 0.000000 142.470000 1.100000 ;
      RECT 140.910000 0.000000 141.240000 1.100000 ;
      RECT 139.680000 0.000000 140.010000 1.100000 ;
      RECT 138.450000 0.000000 138.780000 1.100000 ;
      RECT 137.220000 0.000000 137.550000 1.100000 ;
      RECT 135.990000 0.000000 136.320000 1.100000 ;
      RECT 134.760000 0.000000 135.090000 1.100000 ;
      RECT 133.530000 0.000000 133.860000 1.100000 ;
      RECT 0.000000 0.000000 132.630000 1.100000 ;
    LAYER met5 ;
      RECT 0.000000 152.830000 280.800000 280.460000 ;
      RECT 4.100000 149.170000 280.800000 152.830000 ;
      RECT 4.100000 148.030000 276.700000 149.170000 ;
      RECT 0.000000 144.370000 276.700000 148.030000 ;
      RECT 0.000000 141.850000 280.800000 144.370000 ;
      RECT 4.100000 137.050000 276.700000 141.850000 ;
      RECT 0.000000 0.000000 280.800000 137.050000 ;
  END
END protection_macro

END LIBRARY
